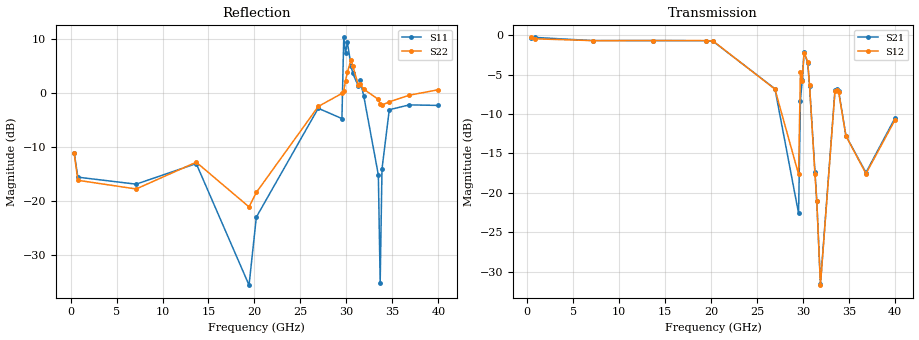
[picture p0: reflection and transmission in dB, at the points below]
! Network Analyzer HP8722ES.07.66: Jul 25, 2000 Serial No. US39175408
! 26 Oct 2004  16:17:48
! Frequency  S11  S21  S12  S22
# HZ  S  DB R  50
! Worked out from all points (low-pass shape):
!   201 points, 400 MHz to 40 GHz, reference 50 ohm
!   highest |S21| = -0.27 dB at 796 MHz (marker M1); lowest = -31.6 dB at 31.88 GHz (marker M2)
!   |S21| within 3 dB of the highest: start of sweep to 24.92 GHz; 30.04 GHz to 30.47 GHz (429.8 MHz wide, 1.42 % of centre)
!   lowest |S11| = -35.7 dB at 19.41 GHz (marker M3), VSWR 1.03, Z = 50.6 - j1.55 ohm
!   |S11| at or under -10 dB: start of sweep to 7.481 GHz; 8.065 GHz to 23.24 GHz (15.18 GHz wide, 97 % of centre); 33.28 GHz to 34.02 GHz (737.3 MHz wide, 2.19 % of centre)
!   |S22| runs from -21.3 to 6.3 dB; largest |S21 - S12| = 0.24
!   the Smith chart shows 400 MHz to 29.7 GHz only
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4e8  -11.08 -82.0  -0.39 12.7  -0.28 14.4  -11.21 -76.4
7.96e8  -15.61 -76.4  -0.27 5.1  -0.45 5.7  -16.19 -87.1
7.132e9  -16.91 -94.4  -0.68 -27.9  -0.68 -28.3  -17.80 -110.0
1.3666e10  -13.09 -133.6  -0.67 -40.3  -0.67 -40.1  -12.83 -109.3
1.9408e10  -35.65 -67.8  -0.69 -62.4  -0.68 -62.1  -21.13 -35.3
2.02e10  -23.03 -12.9  -0.76 -69.1  -0.72 -68.4  -18.45 -6.0
2.6932e10  -2.82 -27.9  -6.79 -113.5  -6.84 -114.3  -2.49 3.3
2.9506e10  -4.73 28.1  -22.61 -178.1  -17.65 -153.9  -0.06 25.7
2.9704e10  10.34 -64.6  -8.33 -80.5  -4.61 -65.4  0.43 -51.2
2.9902e10  7.50 -52.2  -5.70 -49.0  -5.83 -48.9  2.32 10.6
3.01e10  9.42 -68.7  -2.18 -57.6  -2.19 -58.9  3.87 13.5
3.0496e10  5.09 -73.2  -3.47 -113.6  -3.34 -112.3  6.18 -31.3
3.0694e10  3.64 102.8  -6.39 -140.2  -6.33 -139.1  5.01 130.9
3.1288e10  1.29 95.5  -17.41 -157.5  -17.67 -158.5  1.48 124.4
3.1486e10  2.37 -83.5  -21.07 -151.3  -21.10 -153.5  1.62 -53.9
3.1882e10  -0.57 -83.9  -31.60 8.7  -31.72 7.7  0.72 -55.4
3.3466e10  -15.21 -124.9  -6.94 -37.9  -7.03 -38.4  -1.17 -52.8
3.3664e10  -35.26 -53.0  -6.85 -50.2  -6.97 -51.3  -2.03 -51.5
3.3862e10  -14.10 22.8  -7.11 -60.0  -7.23 -62.1  -2.24 -47.6
3.4654e10  -3.09 -12.6  -12.77 -95.6  -12.79 -94.8  -1.62 -48.1
3.6832e10  -2.19 -68.2  -17.43 -72.2  -17.57 -72.7  -0.39 13.5
4e10  -2.29 -76.9  -10.48 11.3  -10.72 12.6  0.62 -31.7
